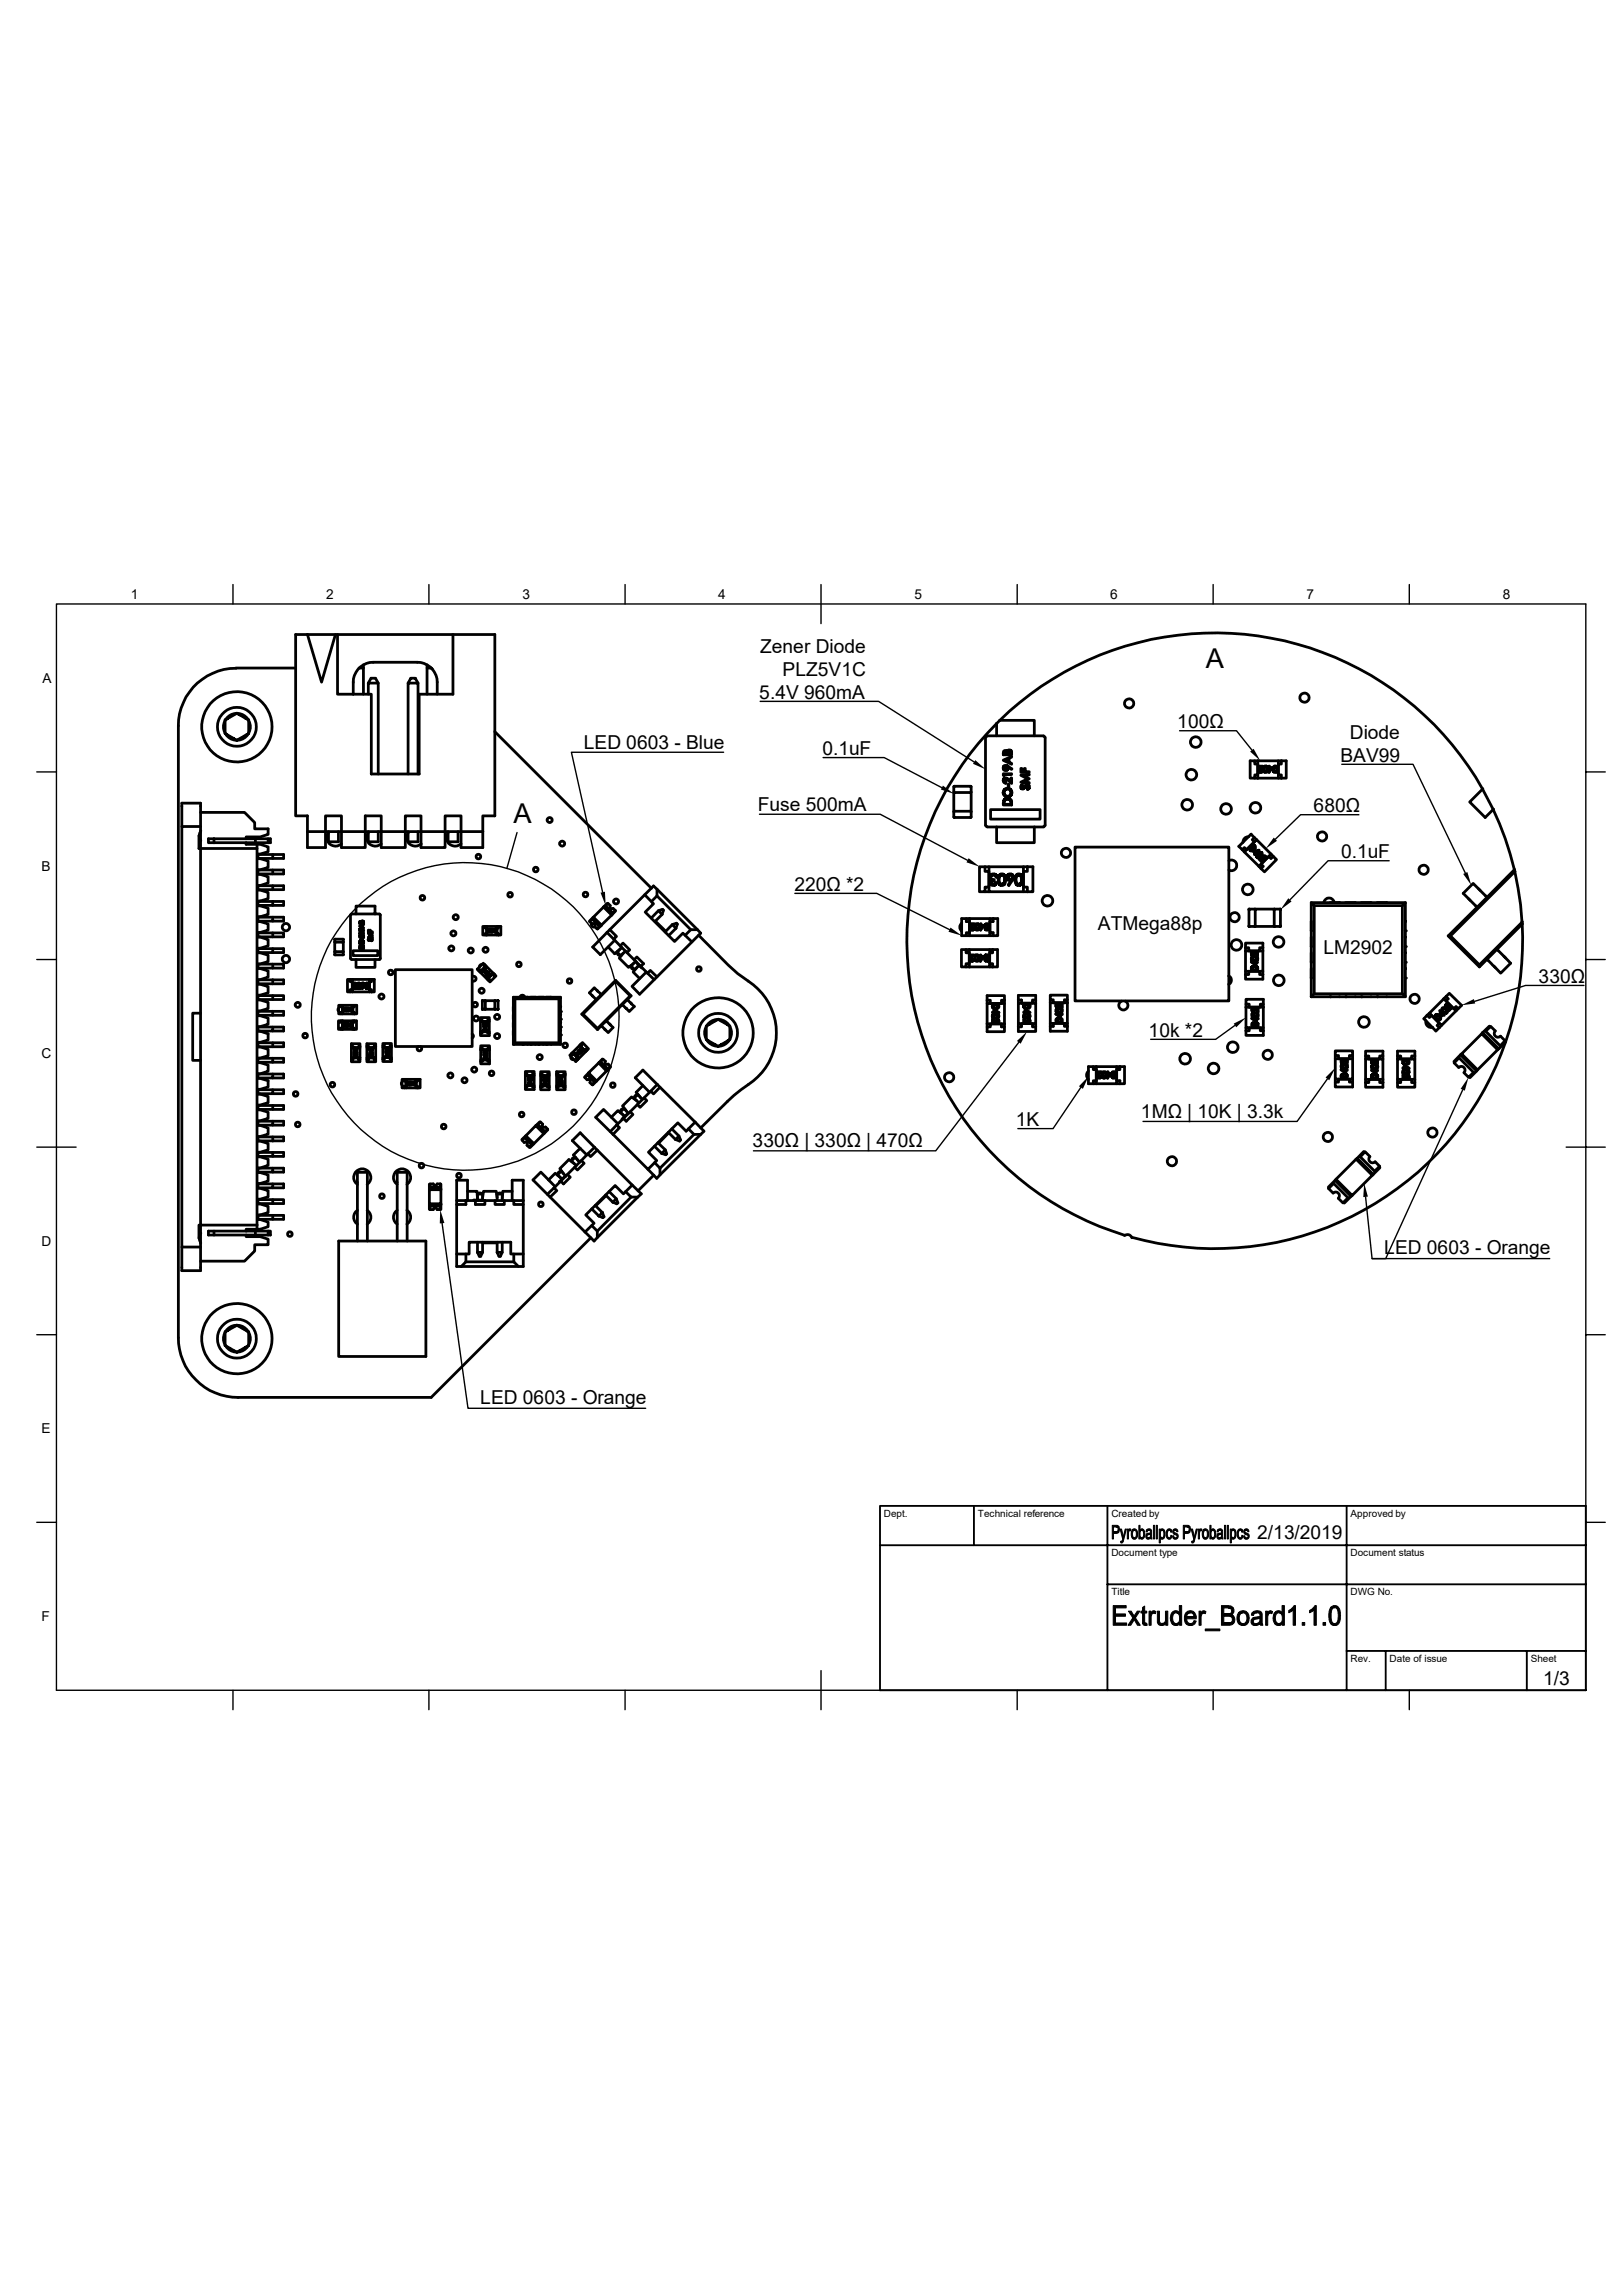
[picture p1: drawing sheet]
<svg xmlns="http://www.w3.org/2000/svg" width="297mm" height="420mm" viewBox="0 0 297 420" stroke-linecap="round" stroke-linejoin="round" font-family="sans-serif">
<defs><g id="words">
<g font-size="5">
<text x="220.6" y="122.3">A</text>
<text x="93.9" y="150.6">A</text>
</g>
<g font-size="3.5">
<text x="139.1" y="119.4">Zener Diode</text>
<text x="143.2" y="123.7">PLZ5V1C</text>
<text x="138.9" y="127.8">5.4V 960mA</text>
<text x="106.8" y="137.2">LED 0603 - Blue</text>
<text x="215.4" y="133.2">100Ω</text>
<text x="247" y="135.2">Diode</text>
<text x="150.5" y="138.1">0.1uF</text>
<text x="245.3" y="139.4">BAV99</text>
<text x="138.7" y="148.5">Fuse 500mA</text>
<text x="240.4" y="148.6">680Ω</text>
<text x="245.4" y="157">0.1uF</text>
<text x="145.4" y="163">220Ω *2</text>
<text x="200.9" y="170.2">ATMega88p</text>
<text x="242.2" y="174.7">LM2902</text>
<text x="281.6" y="179.8">330Ω</text>
<text x="210.2" y="189.7">10k *2</text>
<text x="137.7" y="209.9">330Ω | 330Ω | 470Ω</text>
<text x="185.9" y="206.1">1K</text>
<text x="208.8" y="204.5">1MΩ | 10K | 3.3k</text>
<text x="253.3" y="229.6">LED 0603 - Orange</text>
<text x="87.9" y="257">LED 0603 - Orange</text>
<text x="230.1" y="281.7">2/13/2019</text>
<text x="282.4" y="308.4">1/3</text>
</g>
<g font-size="2.5">
<text x="24" y="109.6">1</text>
<text x="59.7" y="109.6">2</text>
<text x="95.6" y="109.6">3</text>
<text x="131.4" y="109.6">4</text>
<text x="167.3" y="109.6">5</text>
<text x="203.2" y="109.6">6</text>
<text x="239.1" y="109.6">7</text>
<text x="275" y="109.6">8</text>
<text x="7.7" y="125">A</text>
<text x="7.6" y="159.3">B</text>
<text x="7.6" y="193.7">C</text>
<text x="7.6" y="228">D</text>
<text x="7.6" y="262.3">E</text>
<text x="7.6" y="296.6">F</text>
</g>
<g font-size="1.8">
<text x="161.8" y="277.6">Dept.</text>
<text x="178.9" y="277.6">Technical reference</text>
<text x="203.4" y="277.6">Created by</text>
<text x="247.1" y="277.6">Approved by</text>
<text x="203.4" y="284.8">Document type</text>
<text x="247.1" y="284.8">Document status</text>
<text x="203.4" y="292">Title</text>
<text x="247.1" y="292">DWG No.</text>
<text x="247.1" y="304.2">Rev.</text>
<text x="254.3" y="304.2">Date of issue</text>
<text x="280.1" y="304.2">Sheet</text>
</g>
</g></defs>
<g fill="none" stroke="#000" stroke-width=".51">
<path d="M54.1 116.1h36.5v33.2h-2.3v5.8h-3.9v-5.8h-3v5.8h-4.4v-5.8h-2.8v5.8h-4.4v-5.8h-3v5.8h-4.3v-5.8h-2.9v5.8h-3.3v-5.8h-2.2zM56.3 116.1l2.5 8.7 2.6-8.7M61.8 116.1v10.9h2.8M82.9 116.1v10.9h-6.2v14.6h-8.8v-14.6h-3.3M41.2 131.7l1.6-.9a.65 .65 0 0 1 1.1 .1l1.6 .8v2.5l-1.7 1.1a.54 .54 0 0 1-.9-.1l-1.7-1zM43.2 122.3a10.5 10.5 0 0 0-10.6 10.5v112a11 11 0 0 0 11 10.9h35.3l29.2-29.2M43.2 122.3h10.9M64.6 127a5.8 5.8 0 0 1 .6-4 3.7 3.7 0 0 1 3.1-1.8h8.1a3.6 3.6 0 0 1 3.6 3.6v2.2M65.7 122.3h.8M66.5 121.7v5.3M67.4 127v-2h1.8v16.6M67.4 125l.5-.9h.8l.5 .9"/>
<path d="M74.7 125l.5-.9h.8l.5 .9M78.1 121.7v5.3M78.1 122.3h.9l.1 .2M90.6 133.9l28.6 28.7M180.3 135v16M180.4 135l.2-.3h10.4l.2 .3M182.4 132.4a56.3 56.3 0 0 0 23.4 93.7M182.4 132.4v2.3M183 131.8a56.3 56.3 0 0 1 93.9 26.4 56.3 56.3 0 0 1-69.8 68.2M183 131.8h6.3v2.9M183 131.8l-.6 .6M183.6 139.1l1.5-.7v.2l-.4 .2v.7l.4 .2v.2z"/>
<path d="M183.7 137.5l.2-.1 .4 .1 .3-.3h.2l.3 .3v.6h-1.5zM183.8 137.6l.3-.1 .2 .5h-.5zM183.9 139.1l.6-.2v.5zM184.5 137.5h.4l.1 .5h-.6zM191.3 135v16M228.8 139.2h.8v.6h.6v2h-.6v.6h-.8zM229.6 139.2h.6M230.2 139.2h3.7v3.2h-3.7M230.2 139.2v3.2M233.9 139.2h1.5v3.2h-.9M234.5 139.2v.6h-.6v2h.6v.6M33.3 151.3v-4.3h3.4v77.2h10.3"/>
<path d="M36.4 152.9v2.4h10.6M36.4 153l.3 .8M36.7 151.3h-3.4v76.9h3.4M36.7 148.7h8l1.9 1.8v1.2h2.5v1l-1.5 .5h-2.6v.3M36.7 152.1l-.3 .8M38.1 153.5h11.4v.7h-11.4zM39.2 153.5v.7M45 154.2v.3h2M46.7 153.5v.7M47 154.5h.6l1.5 .5v.9l-1.5 .4h-.4v.8h.4l1.5 .5v1.2l-1.5 .4h-.4v.8h.4l1.5 .4v1.2l-1.5 .5h-.4v.8h.4l1.5 .4v1.2l-1.5 .4h-.4v.9h.4l1.5 .4v1.1l-1.5 .5h-.4v.9h.4l1.5 .4v1.1l-1.5 .4h-.4v.9h.4l1.5 .5v1.1l-1.5 .4h-.4v.9h.4l1.5 .4v1.2l-1.5 .4h-.4v.9h.4l1.5 .4v1.1l-1.5 .5h-.4v.8h.4l1.5 .5v1.1l-1.5 .4h-.4v.9h.4l1.5 .4v1.2l-1.5 .4h-.4v.9h.4l1.5 .4v1.2l-1.5 .4h-.4v.8h.4l1.5 .5v1.1l-1.5 .5h-.4v.8h.4l1.5 .4v1.2l-1.5 .4h-.4v.9h.4l1.5 .4v1.1l-1.5 .5h-.4v.9h.4l1.5 .4v1.1l-1.5 .4h-.4v.9h.4l1.5 .5v1.1l-1.5 .4h-.4v.9h.4l1.5 .4v1.2l-1.5 .4h-.4v.9h.4l1.5 .4v1.2l-1.5 .4h-.4v.8h.4l1.5 .5v1.1l-1.5 .5h-.4v.8h.4l1.5 .4v1.2l-1.5 .4h-.4v.9h.4l1.5 .4v1.2l-1.5 .4h-.4v.9h.4l1.5 .4v1.1l-1.5 .5h-.4v.8h.4l1.5 .5v1.1l-1.5 .4h-.4v.9h.4l1.5 .4v.9l-1.5 .5h-.6M47 154.5v70.5M47.2 156.4h4.7v.7h-4.7"/>
<path d="M47.2 159.2h4.7v.7h-4.7M49.1 153.5v.7M49.9 156.4v.7M49.9 159.2v.7M56.3 152.2h32M60.1 152.4a1.57 1.57 0 0 0 .3 2.1 1.57 1.57 0 0 0 2.1-.1M60.1 152.2v1.9h1.8v-1.9M67.4 152.4a1.57 1.57 0 0 0 .2 2.1 1.57 1.57 0 0 0 2.2-.1M67.4 152.2v1.9h1.8v-1.9M74.7 141.6v-16.6h1.8v16.6M74.7 152.2v1.9h1.8v-1.9M74.7 152.4a1.57 1.57 0 0 0 .3 2.1 1.57 1.57 0 0 0 2.1-.1"/>
<path d="M82 152.4a1.57 1.57 0 0 0 .2 2.1 1.57 1.57 0 0 0 2.2-.1M82 152.2v1.9h1.8v-1.9M174.5 145h3.2v3.5h-3.2zM174.6 145v-1.1h3v1.1M174.6 148.5v1.1h3v-1.1M179.2 158.6h1.1v.9h.7v2.8h-.7v.9h-1.1zM180.3 158.6h.7M180.4 151l.2 .3M180.6 151.3h10.4M181 158.6h6.3v4.6h-6.3zM181.3 148.2h9v1.7h-9zM182.4 151.3v2.9h6.9v-2.9"/>
<path d="M183.6 141.6h1.5v.1h-1.3v.3l-.2-.1zM183.6 142.5l.3-.1h.4l.7 .6v-.6h.1v1l-.7-.7a.34 .34 0 0 0-.6 0 .34 .34 0 0 0 .3 .5v.1l-.4-.1-.1-.4zM183.7 140.2l.5-.1 1 .6-.1 .1-.6-.4-.1 .4-.2 .2h-.3l-.3-.2zM183.8 140.3l.1-.1 .4 .1v.4l-.2 .2-.2-.1zM183.8 146.3l.4-.2 .7 .1 .2 .4v.7h-1.5zM183.9 146.4l.3-.2 .5 .1 .3 .3v.6h-1.2zM184.5 143.5h.1v.6h-.1zM186.1 160l.5-.1 .3 .3a1.71 1.71 0 0 1 0 1.6l-.6 .3-.5-.6v-.9zM186.8 140.6h.2v.6h.5v-.6h.1v.6h.7v.2h-1.5zM186.8 141.9l1.5-.2v.1l-1.1 .1 1.1 .6-1.1 .6 1.1 .1v.2l-1.5-.2 1.3-.7zM186.9 143.8l.1-.2 .2 .2a.23 .23 0 0 0-.3 .3 .23 .23 0 0 0 .4 0l.4-.4 .4-.1 .2 .2 .1 .4-.4 .3v-.1l.2-.3-.1-.3-.2-.1-.3 .3a.47 .47 0 0 1-.6 .4l-.2-.3zM187.3 158.6h1.7v4.6h-1"/>
<path d="M188 158.6v.9h-.7v2.8h.7v.9M191.2 151l-.2 .3M196.7 155h28.2v28.2h-28.2zM224.9 157.5a.97 .97 0 0 1 1.4 .9 .97 .97 0 0 1-1.4 .8M227.3 155.5l.4 .4M228.5 153.1a.98 .98 0 0 0-1 1.1M228.9 155.2l.4-.4 .3 .2-.2 .4-.2 .2-.4-.1zM228.9 154.9l.4-.2 .4 .2v.4l-.5 .4h-.3l-.2-.2v-.3zM229.3 155.8l1.1-.2-.5 .6 .1 .1-.4 .1h-.1l.2-.2zM229.5 153.3l-.3 .4 .3 .4-1.4 1.4-.4-.4-.4 .4M229.5 153.3l-.6-.6-2.2 2.2 .6 .6M229.5 153.3l.5 .4"/>
<path d="M229.6 155.9l.6-.2-.4 .4zM229.6 142.4h.6M230.1 156.4l.5-.4 .2 .2v.3l-.4 .4-.4-.1zM230.2 156.2l.3-.2h.3l.2 .2v.2l-.5 .5-.3 .1-.3-.2zM230.3 140.2h.8l-.6 .7a.25 .25 0 0 0 .1 .4 .25 .25 0 0 0 .3-.3l.2 .1-.3 .3h-.3l-.2-.2 .1-.4 .4-.5zM230.4 157.2l1-.1a.25 .25 0 0 0 0-.4 .25 .25 0 0 0-.3 .1v-.2h.3a.37 .37 0 0 1 .2 .4 .37 .37 0 0 1-.3 .3h-.7l.4 .4-.1 .1zM230.4 158.5l.4 .5M230.8 158.2l1.4-1.5 .4 .4 .4-.4 .6 .6-2.2 2.3-.6-.6 .4-.5zM231.3 140.3l.2-.1 .4 .1 .1 .7-.2 .3h-.5l-.1-.4zM231.4 140.4l.3-.1 .2 .2v.6l-.3 .2-.3-.3zM232.2 140.2h.1v.3h.6l-.7 .9v-.8h-.1zM232.3 140.6h.4l-.4 .5z"/>
<path d="M232.6 156.3l-2.6-2.6-2.3 2.2 2.7 2.6M232.6 156.3l-2.2 2.2M232.6 156.3l.4 .4M233.2 140.3h.3l.1 .2v.5l-.2 .3-.3-.2zM233.2 140.2h.3l.2 .3v.6l-.2 .3-.4-.1-.1-.3v-.5zM233.9 142.4h.6M271.4 144.4l-2.5 2.4 2.9 2.8 1.5-1.5M277.2 159.1l-12.2 12.2M277.2 159.5l-11.8 11.8M47.2 170.7h4.7v.8h-4.7M47.2 176.4h4.7v.8h-4.7M47.2 162.1h4.7v.7h-4.7"/>
<path d="M47.2 165h4.7v.7h-4.7M47.2 167.9h4.7v.7h-2M47.2 173.6h4.7v.7h-2M47.2 179.3h4.7v.7h-4.7M49.9 167.9v.7h-2.7M49.9 173.6v.7h-2.7M49.9 162.1v.7M49.9 165v.7M49.9 170.7v.8M49.9 176.4v.8M49.9 179.3v.7M61.3 172.4h1.5v1.8h-1.5z"/>
<path d="M61.3 172.4v-.5h1.5v.5M61.3 174.2v.6h1.5v-.6M63.6 179.2h.5v.5h.4v1.4h-.4v.4h-.5zM64.1 179.2h.4M64.1 167.4v8M64.2 175.4l.1 .2M64.3 175.6h5.2M64.3 167.3h5.2M64.3 167.3l-.1 .1M64.5 179.2h3.1v2.3h-3.1zM64.6 174h4.5v.9h-4.5zM65.2 167.3v-1.5h3.4v1.5"/>
<path d="M65.2 175.6v1.4h3.4v-1.4M65.4 180l.2-.1a.53 .53 0 0 1 .4 .4 .53 .53 0 0 1-.1 .5l-.4 .1-.2-.2v-.6zM65.8 169.5l.7-.4-.2 .2v.4l.2 .1zM65.8 170.7l.7 .1-.6 .1zM65.8 171.2l.3-.1 .4 .4v-.4v.5l-.3-.3a.2 .2 0 0 0-.4 0 .19 .19 0 0 0 .2 .3l-.2-.1zM65.8 168.7l.7-.1v.4h-.7zM65.9 170.1h.2v.2h-.2zM65.9 172.2l.4-.2 .2 .3v.3l-.1 .2h-.4a.44 .44 0 0 1-.1-.6zM65.9 170h.2l.4 .3-.3-.2v.2l-.3 .1-.1-.1zM65.9 173.1h.6v.5h-.7zM65.9 168.7h.2v.2h-.2zM65.9 173.1h.4l.2 .4h-.6z"/>
<path d="M66 169.5l.2-.1v.2zM66 172.2h.4a.36 .36 0 0 1-.2 .6 .38 .38 0 0 1-.2-.6zM66 171.5v.1M66.2 180a.35 .35 0 0 1 .5 0 .35 .35 0 0 1-.1 .5l-.4 .4 .3-.4-.4-.1zM66.2 171.7l.1 .3zM66.2 168.7h.3v.2h-.3zM67.4 170.2l.1 .3h.2l.1-.3v.3l.4 .1h-.8zM67.4 170.9l.8-.1-.6 .1 .6 .3-.6 .3 .6 .1-.8-.1 .6-.3zM67.4 171.8h.2l-.2 .2h.2l.3-.3h.2v.4h-.2l.2-.3h-.2a.23 .23 0 0 1-.3 .3 .23 .23 0 0 1-.2-.3zM67.6 179.2h.9v2.3h-.5M68 179.2v.5h-.4v1.4h.4v.4M69.5 167.3l.1 .1v8l-.1 .2"/>
<path d="M72.3 177.5h14.1v14h-14.1zM86.4 178.7a.48 .48 0 0 1 .6 .1 .48 .48 0 0 1 .1 .5l-.4 .3-.3-.1M87.8 177.9l1.1-1.1 1.4 1.3-1.1 1.1zM88.2 176.5l-.4 .2-.1 .3M88.3 169.5h.5v.3h.3v1.1h-.3v.2h-.5zM88.4 177.5l.2-.2 .2 .1v.1l-.3 .3-.1-.1zM88.5 177.3h.3l.1 .1-.3 .4-.3-.1zM88.6 177.8l.6-.1-.4 .4zM88.7 176.6l-.1 .2 .1 .2-.6 .7-.3-.2-.2 .2M88.7 176.6l-.3-.3-1.1 1.1 .5 .5M88.7 176.6l.2 .2M88.8 177.8h.3l-.2 .2z"/>
<path d="M88.8 169.5h.3M88.8 171.1h.3M89 178.2l.2-.2h.2l-.2 .4h-.2zM89.1 178l.1-.1 .3 .1-.1 .3-.2 .1h-.3zM89.1 169.5h1.8v1.6h-1.8M89.1 169.5v1.6M89.2 178.6l.5-.1v-.1l-.2-.1v-.1l.3 .1-.1 .3h-.4l.2 .2zM89.2 170h.3l-.3 .3v.3l.3-.2-.1 .2-.2-.1v-.2l.2-.2zM89.2 179.2l.2 .2M89.4 179l.7-.7 .2 .2 .2-.2 .3 .3-1.1 1.1-.3-.3 .2-.2zM89.6 170.1l.1-.1a.3 .3 0 0 1 .3 .2 .3 .3 0 0 1-.1 .3l-.3 .1zM89.7 170.1h.1l.1 .1-.1 .4-.2-.2z"/>
<path d="M90.1 170v.1h.3l-.3 .5zM90.1 170.2h.2l-.2 .3zM90.3 178.1l.2 .2M90.5 170.1l.1-.1a.33 .33 0 0 1 .3 .2 .33 .33 0 0 1-.1 .4l-.3-.1zM90.6 170.1l.2 .1-.1 .4-.2-.2zM90.9 169.5h.8v1.6h-.5M90.9 171.1h.3M91.2 169.5v.3h-.3v1.1h.3v.2M107.9 168.7l.5-.5 1.3 1.3-.5 .5-.4-.4 .1-.4-.4-.2-.2 .1zM108.2 169a.48 .48 0 0 0 .1 .5 .48 .48 0 0 0 .6 .1M108.5 167.9l-.6 .7M108.6 167.9h-.1l1.5 1.5"/>
<path d="M110 169.4l-.7 .6v-.1M110.1 169.3l-.1 .1M110.4 166l.1-.1 1.5 1.5-.1 .1M110.4 166l-1.8 1.9 1.5 1.4 1.8-1.8M110.4 166l1.5 1.5M111.1 170.6l7.4 7.5M111.1 170.6l-2.6 2.7 1.4 1.4 2.6-2.6M111.2 165.4l-.7 .5M111.3 165.3l.4 .4-.1 .2 .2 .4 .4-.1 .4 .4-.5 .5-1.3-1.3zM111.3 173.3l1.2 1.2 1-.9M111.6 170.1l1.2 1.3-.5 .5M112.5 166.7l.1 .1-.6 .6"/>
<path d="M112.6 179.4l-6.1 6.2M112.6 179.6v-.2l2.9 2.8h-.2M112.9 174.2a.66 .66 0 0 0 .7 .7M113.5 173.1l.5-.5 1.2 1.2-.5 .5M113.8 173.4l-.9 .8 .7 .7 .9-.9M114.1 174.4l-.8 .9 1.7 1.7 1-.7M115.4 176.7a.66 .66 0 0 0 .8 .8M116 175.6l.5-.5 1.3 1.3-.5 .5M116.3 175.9l-.8 .9 .6 .6 .8-.8M116.4 176l.7 .8M116.8 176.8l-.9 1.1 1.2 1.2M117.1 176.7v.1l.4 .3"/>
<path d="M118 163.7l1.6 1.7-1.5 1.5 5.3 5.4 1.6-1.5 1.6 1.6-6.4 6.4-1.2-1.2-.5 .5M118.3 177.9l-2.6 2.6 1.4 1.4 3.1-3.1M118.5 178.1l1.2 1.2M119.9 168.6l1.9 1.8M120.2 162.7v1.3l-1 1M120.2 164l6.2 6.1M120.5 166.7l.7-.3 .2 .2-.2 .7zM120.5 166.7l-1.3 1.3M121.2 167.3l-1.4 1.4M123 169.2l.8-.2 .2 .1-.3 .8zM123 169.2l-1.3 1.4M123.7 169.9l-1.3 1.3"/>
<path d="M125.4 171.2l1-1.1h1.2l.6 .7-1.6 1.6M127.6 170.1l-8-8-8.5 8.5M127.8 171.2l5.5 5.4 1.7 1.6a17.2 17.2 0 0 1 5.1 4.5 11.3 11.3 0 0 1-3.2 15.8 45.7 45.7 0 0 0-8.7 7.9M175.9 173.8h.9v.6h.6v2h-.6v.6h-.9zM176 168.1h.8v.6h.6v2h-.6v.5h-.8zM176 168.9a1 1 0 0 0 0 1.5M176.8 173.8h.6M176.8 177h.6M176.8 168.1h.6M176.8 171.2h.6M177.4 173.8h3.7v3.2h-3.7M177.4 173.8v3.2"/>
<path d="M177.4 168.1h3.7v3.1h-3.7M177.4 168.1v3.1M177.5 174.8h.8l-.7 .6a.27 .27 0 0 0 .2 .4 .27 .27 0 0 0 .3-.2 .31 .31 0 0 1-.2 .3 .31 .31 0 0 1-.4-.2v-.3l.5-.5h-.5zM177.5 169h.8l-.6 .8 .1 .3h.3l.2-.3-.2 .4a.37 .37 0 0 1-.5-.1 .37 .37 0 0 1 .1-.5l.4-.4h-.6zM178.5 174.8l.4-.1 .2 .2 .1 .7a.43 .43 0 0 1-.7 .3l-.1-.3v-.6zM178.6 169.1l.4-.1 .2 .3v.6l-.3 .3h-.2l-.2-.2-.1-.6zM178.6 174.9l.3-.1 .1 .2v.6l-.1 .2-.4-.2zM178.6 169.2h.3a.59 .59 0 0 1 .2 .8l-.2 .1-.3-.1zM179.4 174.8l.1 .2h.5l-.6 .9v-.8h-.2v-.1h.2zM179.5 169v.3h.6l-.6 .9v-.8h-.2l.2-.1zM179.5 175.1h.3l-.3 .5zM179.5 169.4h.4l-.4 .5z"/>
<path d="M180.3 174.8l.3-.1a.84 .84 0 0 1 .2 1.1l-.1 .1a.42 .42 0 0 1-.6-.4zM180.3 163.2h.7M180.3 175l.3-.2 .2 .2v.6l-.2 .2-.3-.1zM180.3 169.2l.4-.2 .2 .2 .1 .7-.3 .3h-.3l-.2-.3zM180.3 169.3a.26 .26 0 0 1 .3-.2 .26 .26 0 0 1 .2 .2v.7l-.3 .1-.2-.3zM181.1 173.8h1.4v3.2h-.8M181.1 177h.6M181.1 168.1h1.5v3.1h-.9M181.1 171.2h.6M181.2 160.2l.3-.2 .5-.1 .5 .5v.1h-.2l-.3-.4h-.4l-.2 .2-.1 .4 .3 .3h.3v.2l-.5 .1v.4l.5 .1 .5-.3-.3 .5h-.5a.55 .55 0 0 1-.3-.8l.1-.1-.3-.4zM181.7 173.8v.6h-.6v2h.6v.6M181.7 168.1v.6h-.6v2h.6v.5"/>
<path d="M182.8 160.2l.4-.3h.3l.3 .3a1.71 1.71 0 0 1 0 1.6l-.6 .3-.4-.3-.1-.4v-.9zM183 160.3l.1-.1a.43 .43 0 0 1 .6 .2l.2 .6-.1 .5-.2 .3h-.4l-.2-.1-.2-.4v-.6zM184.3 160.2l.4-.3h.3l.3 .2a.59 .59 0 0 1 0 .8l-.7 1.2-.1-.2 .5-.8h-.4l-.3-.2zM186.1 160.3l.1-.1a.43 .43 0 0 1 .6 .2l.1 .5v.6l-.2 .3h-.4l-.4-.5v-.6zM187.3 163.2h.7M224.8 178.6a.83 .83 0 0 1 .5 .8 .83 .83 0 0 1-.5 .7M227.9 174v3.8h3.2v-3.8M227.9 173.4h.6v.6h2v-.6h.6M227.9 173.4v-.8h3.2v1.4M227.9 178.4h.6v-.6h2v.6h.6M227.9 174h3.2M227.9 173.4v.6"/>
<path d="M227.9 177.8v.6M228.6 169.5h.1M228.6 166.4v.1M229 177l.3-.2h.6l.2 .2 .1 .3-.2 .2-.7 .1-.3-.2zM229 176.1h.7l.2-.2v.2h.2h-.2v.6zM229 175.2l.3-.2h.5l.4 .3v.3l-.4 .2h-.5l-.3-.2zM229 174.3l.4-.1 .6 .5 .1-.5v.7l-.7-.6-.3 .1v.3l.3 .2-.3-.1-.1-.1zM229.1 175.3l.3-.2 .3 .1a.26 .26 0 0 1 .3 .2 .26 .26 0 0 1-.3 .3 .39 .39 0 0 1-.5-.1zM229.2 177h.7l.1 .3-.1 .2h-.6l-.2-.2zM229.3 176.1h.4v.4zM229.6 166.4l.1 .1M229.7 166.4h3.5v3.1h-3.5z"/>
<path d="M229.7 166.4h-1.1v3.1h1.1M229.7 169.5h-.1M231.1 177.8v1.4h-3.2v-.8M233.2 166.4h1.1v3.1h-1.1M233.2 169.5h.1M233.3 166.4l-.1 .1M234.2 166.4l.1 .1M234.3 169.5h-.1M239.9 165.2h17.3M239.9 174.4l.1 1.7M239.9 168.6l.1 1.7M239.9 171.5l.1 1.7"/>
<path d="M239.9 177.3l.1 1.7M240.5 165.7h16.1M242.2 165.2a.98 .98 0 0 1 1-.9 .98 .98 0 0 1 1 .9M256.6 165.7l.6-.5v17.2l-.6-.5zM257.2 176.1h.1M257.2 173.2h.1M257.2 170.3h.1M257.2 179h.1M257.2 177.3h.1M257.2 168.6h.1M257.2 171.5h.1M257.2 174.4h.1"/>
<path d="M270.7 176.6l-5.3-5.3h-.4l5.7 5.7M272.1 164.2l-2.5-2.5-1.8 1.8 2.5 2.5M273.9 173.7l2.5 2.6-1.8 1.8-2.5-2.5M278.6 168.7l-7.9 7.9v.4l3.2-3.3M278.6 169.1l-4.7 4.6M36.7 185.4h-1.4v8.7h1.4M47.2 182.2h4.7v.7h-4.7M47.2 188h4.7v.7h-2M47.2 185.1h4.7v.7h-2M47.2 190.8h4.7v.8h-4.7M47.2 193.7h4.7v.7h-2M47.2 196.6h4.7v.7h-2"/>
<path d="M47.2 199.4h4.7v.8h-2M49.9 199.4v.8h-2.7M49.9 196.6v.7h-2.7M49.9 193.7v.7h-2.7M49.9 188v.7h-2.7M49.9 185.1v.7h-2.7M49.9 182.2v.7M49.9 190.8v.8M61.9 186.8h.5v.3h.3v1h-.3v.3h-.5zM62 184h.4v.3h.3v1h-.3v.2h-.4zM62 184.4l-.2 .3 .2 .4M62.4 186.8h.3"/>
<path d="M62.4 188.4h.3M62.4 184h.3M62.4 185.5h.3M62.7 186.8h1.8v1.6h-1.8M62.7 186.8v1.6M62.7 184h1.9v1.5h-1.9zM62.7 187.3h.4l-.3 .4 .1 .1 .2-.1-.1 .2-.3-.1 .3-.4zM62.7 184.4h.5l-.4 .4 .1 .2 .2-.1-.1 .1h-.2v-.3l.2-.2zM63.2 187.4l.2-.1 .1 .1v.5l-.3-.1zM63.2 187.4h.3l-.1 .4h-.2zM63.2 184.5l.3-.1v.2a.3 .3 0 0 1 .1 .3 .3 .3 0 0 1-.3 .1zM63.3 184.5h.2a.22 .22 0 0 1 .1 .3 .22 .22 0 0 1-.4 .1z"/>
<path d="M63.7 187.3v.1h.3l-.3 .5zM63.7 187.5h.2l-.2 .2zM63.7 184.4l.1 .2h.2l-.3 .4zM63.8 184.7h.1l-.1 .2zM64.1 187.3h.1a.34 .34 0 0 1 .2 .5h-.3zM64.1 181.5h.4M64.1 184.5h.3a.3 .3 0 0 1 0 .4 .3 .3 0 0 1-.3 .1zM64.1 187.4h.2a.25 .25 0 0 1 .1 .3 .25 .25 0 0 1-.2 .1zM64.2 184.5a.2 .2 0 0 1 .2 .3 .2 .2 0 0 1-.3 .1zM64.3 193.9h.3v-.3h1v.3h.3v.4h-1.6zM64.3 193.6v-1.9h1.6v1.9M64.3 191.5h.3v.2h1v-.2h.3"/>
<path d="M64.3 193.6h1.6M64.3 193.6v.3M64.5 186.8h.7v1.6h-.4M64.5 188.4h.3M64.6 184h.7v1.5h-.4M64.6 180l.3-.1 .3 .3-.2-.2a.23 .23 0 0 0-.4 .2 .23 .23 0 0 0 .3 .2l-.2 .2v.2h.2l.3-.1v.1l-.5 .1-.1-.1 .1-.3-.2-.2zM64.6 185.5h.3M64.8 192.8l.1-.1a.24 .24 0 0 1 .3 0 .24 .24 0 0 1 .1 .3l-.4 .1zM64.8 193.2l.3 .3 .2-.1-.1-.2h.1l.1 .3h-.2l-.3-.2-.1 .2zM64.8 192.9l.3-.2 .2 .3h-.4zM64.8 186.8v.3h-.3v1h.3v.3M64.8 192l.4-.1 .1 .2-.4 .1z"/>
<path d="M64.9 191.9a.26 .26 0 0 1 .4 0 .26 .26 0 0 1-.2 .4 .26 .26 0 0 1-.3-.4zM64.9 184v.3h-.3v1h.3v.2M64.9 192.3l.5 .3-.5 .1-.1-.1 .1-.1zM65 192.4l.2 .1h-.2zM65.4 180.1l.3-.1 .2 .1v.4l-.2 .3-.3-.1zM65.9 191.5v-.5h-1.6v.7M65.9 191.5v.2M65.9 193.6v.3M66.2 180.1l.3-.1 .1 .2a.22 .22 0 0 1-.2 .2 .22 .22 0 0 1-.2-.3zM66.9 180l.3-.1 .3 .1v.7l-.2 .2h-.2l-.2-.1zM67 180.1l.1-.1 .3 .1v.5l-.1 .2-.3-.1zM67.1 191.7h1.6v1.9h-1.6z"/>
<path d="M67.1 193.9h.3v-.3h1.1v.3h.2v.4h-1.6zM67.1 191.4h.3v.3h1.1v-.3h.2M67.1 193.6v.3M67.6 181.5h.4M67.6 192.8l.5-.1 .1 .3-.4 .1zM67.6 191.9l.5-.1 .1 .3-.1 .1h-.4zM67.6 193.1l.4 .4 .2-.1-.2-.2h.2v.3h-.3l-.2-.2-.1 .2zM67.7 192.8l.4-.1 .1 .3h-.4zM67.7 191.9a.25 .25 0 0 1 .3-.1 .25 .25 0 0 1 .2 .3l-.4 .1zM67.8 192.2l.4 .4h-.6l.2-.1zM67.8 192.4l.3 .1h-.3zM68.7 191.4v-.4h-1.6v.7"/>
<path d="M68.7 191.4v.3M68.7 193.6v.3M70.1 191.7h1.5v1.8h-1.5zM70.1 191h1.5v.4h-.2v.3h-1v-.3h-.3zM70.1 193.8h.3v-.3h1v.3h.2M70.1 191.4v.3M70.1 193.5v.3M70.6 192.7h.6h-.2v.3zM70.6 192.3l.5-.1 .1 .3-.5 .1zM70.6 191.8h.2l.3 .2 .1-.2v.4l-.4-.4-.1 .1 .1 .2h-.1zM70.6 193.2l.4-.1 .2 .2-.2 .2h-.3zM70.7 192.3h.4v.2h-.4z"/>
<path d="M70.7 193.2l.3-.1 .1 .2-.4 .1zM70.7 192.7h.3v.2zM71.6 193.5v.8h-1.5v-.5M71.6 191.4v.3M73.6 197.5h.4v.3h.3v1h-.3v.3h-.4zM73.6 198l-.2 .2 .2 .4M74 197.5h.3M74 199.1h.3M74.3 197.5h1.9v1.6h-1.9zM74.3 198h.5l-.4 .3 .1 .2 .2-.1-.1 .2-.2-.1v-.2l.2-.3zM74.8 198l.3 .1a.3 .3 0 0 1 .1 .3 .3 .3 0 0 1-.3 .2l-.1-.1zM74.9 198.1l.2-.1v.2l-.1 .3-.2-.1z"/>
<path d="M75.3 198l.1 .1h.2l-.3 .5zM75.4 198.2h.1l-.1 .3zM75.7 198h.3v.1a.3 .3 0 0 1-.2 .5l-.1-.1zM75.8 198.1a.2 .2 0 0 1 .2 .2 .2 .2 0 0 1-.2 .2zM76.2 197.5h.7v1.6h-.4M76.2 199.1h.3M76.5 197.5v.3h-.3v1h.3v.3M76.6 191.5l-.3 .4 .1 .2a.43 .43 0 0 0 .5 .2 .43 .43 0 0 0 .3-.4l-.3-.4M86.4 189.2l.3 .4-.3 .4M87.9 186.9h1.6v1.9h-1.6zM87.9 186.2h1.6v.4h-.3v.3h-1v-.3h-.3zM87.9 189.1h.3v-.3h1v.3h.3"/>
<path d="M87.9 186.6v.3M87.9 188.8v.3M88 191.4h1.6v.4h-.3v.3h-1v-.3h-.3zM88 192.1v1.9h1.6v-1.9M88 194.3h.3v-.3h1v.3h.3M88 192.1h1.6M88 191.8v.3M88 194v.3M88.3 184.7h.1M88.3 183.1v.1M88.5 188l.4-.1 .1 .1h-.1v.3zM88.5 188.4l.4-.1 .2 .3-.5 .1z"/>
<path d="M88.5 187.1l.2-.1 .3 .3v-.3v.4l-.3-.3h-.2l.1 .3zM88.5 187.5h.4l.2 .2-.5 .1zM88.5 193.1l.4-.1 .2 .2h-.2v.2zM88.5 193.6l.1-.1a.28 .28 0 0 1 .3 0 .28 .28 0 0 1 .1 .3h-.5zM88.5 187.6l.4-.1a.21 .21 0 0 1-.1 .3 .21 .21 0 0 1-.3-.2zM88.5 192.2h.2l.3 .2 .1-.2v.3l-.3-.3-.2 .1v.2zM88.5 188.5l.4-.1a.21 .21 0 0 1-.1 .3 .21 .21 0 0 1-.3-.2zM88.5 193.1h.1M88.6 192.7h.4a.22 .22 0 0 1-.1 .2 .22 .22 0 0 1-.3 0zM88.6 192.7l.4-.1 .1 .3-.2 .1h-.3zM88.6 193.6l.4-.1v.3h-.4zM88.6 188h.3v.2z"/>
<path d="M88.6 193.2h.3v.1zM88.7 192.5h.1M88.8 183.1v.1M88.8 183.1h1.8v1.6h-1.8zM88.8 183.1h-.5v1.6h.5M88.8 184.7h.1M89.5 188.8v.7h-1.6v-.4M89.5 186.6v.3M89.6 194v.7h-1.6v-.4M89.6 191.8v.3M90.6 183.1h.5v1.6h-.5M90.6 184.7h.1"/>
<path d="M90.6 183.1v.1M91.1 183.1v.1M91.1 184.7h.1M93.9 182.5h8.7M93.9 187.1l.1 .9M93.9 184.2l.1 .9M93.9 185.7l.1 .8M93.9 188.6l.1 .8M94.2 182.8l-.3-.3v8.6M94.2 182.8v8M94.2 182.8h8.1M95.1 182.5a.48 .48 0 0 1 .5-.4 .48 .48 0 0 1 .5 .4"/>
<path d="M95.7 191.1h.1M96.1 196.8h1.6v1.9h-1.6zM96.1 196.1h1.6v.4h-.2v.3h-1.1v-.3h-.3zM96.1 199h.3v-.3h1.1v.3h.2M96.1 196.5v.3M96.1 198.7v.3M96.5 191.1h.1M96.7 197.8l.4-.1 .1 .2h-.1v.2zM96.7 197.4l.5-.1 .1 .3-.5 .1zM96.7 198.3l.5-.1 .1 .3-.4 .1-.2-.1zM96.7 196.9h.2l.3 .2v-.2v.3l-.3-.3-.2 .1 .1 .2zM96.7 198.3l.5-.1v.3h-.4z"/>
<path d="M96.7 197.4h.4l.1 .2-.3 .1zM96.8 197.9h.3v.1zM97.1 191.1h.1M97.7 198.7v.7h-1.6v-.4M97.7 196.5v.3M98 191.1h.1M98.6 191.1h.1M98.9 196.9h1.6v1.8h-1.6zM98.9 196.1h1.6v.5h-.3v.3h-1v-.3h-.3zM98.9 199h.3v-.3h1v.3h.3M98.9 196.6v.3M98.9 198.7v.3"/>
<path d="M99.4 191.1h.1M99.4 197.9l.5-.1 .1 .1h-.1v.3zM99.4 198.3h.1a.27 .27 0 0 1 .4-.1 .27 .27 0 0 1 0 .4 .27 .27 0 0 1-.4-.1zM99.4 197l.3-.1 .3 .2v-.2v.4l-.3-.3-.2 .1 .2 .2-.2-.1zM99.5 197.4h.5a.28 .28 0 0 1-.2 .4 .28 .28 0 0 1-.3-.2zM99.5 197.4h.4l.1 .2-.4 .1zM99.5 198.3h.4l.1 .2h-.4zM99.6 197.9h.2v.2zM100 191.1h.1M100.5 198.7v.7h-1.6v-.4M100.5 196.6v.3M100.8 191.1h.1"/>
<path d="M101.9 196.9h1.5v1.8h-1.5zM101.9 199h.3v-.3h.9v.3h.3v.4h-1.5zM101.9 196.6h.3v.3h.9v-.3h.3M101.9 198.7v.3M102.3 182.8l.3-.3v8.6l-.3-.3zM102.3 190.8h-8.1l-.3 .3h8.7M102.3 197.9l.5-.1 .1 .3-.4 .1zM102.3 198.2l.4 .4 .2-.1-.2-.3 .1 .1 .1 .2-.2 .1-.3-.2-.1 .2zM102.4 197l.4-.1 .1 .3-.2 .1h-.3zM102.4 197.1l.4-.1 .1 .1-.4 .2zM102.4 197.9h.4a.22 .22 0 0 1-.2 .3 .22 .22 0 0 1-.2-.3zM102.4 197.4l.5 .3h-.6h.1z"/>
<path d="M102.5 197.4l.3 .3h-.3zM102.6 188h.1M102.6 186.5h.1M102.6 185.1h.1M102.6 189.4h.1M102.6 188.6h.1M102.6 184.2h.1M102.6 185.7h.1M102.6 187.1h.1M103.4 196.6v-.5h-1.5v.8M103.4 196.6v.3M103.4 198.7v.3"/>
<path d="M104.5 193.3l.1 .5 .4 .1M104.6 192.8l.2 .2 .1-.2 .8 .7-.2 .3 .2 .2M104.6 192.8l-.3 .3 1.1 1.2 .5-.5M104.8 192.6l1.3-1.3 1.1 1.1-1.3 1.4zM104.8 192.6l-.2 .2M105.3 192.8l.2-.1 .2 .2v.4h-.2l-.2-.3zM105.3 192.9h.3l.1 .2a.28 .28 0 0 1-.2 0 .28 .28 0 0 1-.2-.2zM105.7 192.4l.4 .4-.1-.1-.2 .3zM105.8 192.5l.2 .2-.2 .1zM105.9 192.2a.32 .32 0 0 1 .3-.1 .32 .32 0 0 1 .2 .3 .26 .26 0 0 1-.2 .2 .26 .26 0 0 1-.3-.2zM106 192.2h.2l.1 .4h-.2zM106.2 191.9l.3-.1 .1 .5 .2-.1-.2 .2-.1-.5h-.2v.2z"/>
<path d="M106.3 191.1l.3-.3 1.1 1.1-.3 .3-.2-.2-.2 .2-.7-.7 .2-.2zM106.3 191.1l-.2 .2M106.5 185.6h.2l2.6 2.6v.2zM107 197.2l.5-.5 1.3 1.3-.5 .5-.4-.4 .1-.2-.1-.3h-.5zM107.4 192.2l-.2 .2M107.6 196.5l-.5 .6M107.7 196.3l1.9-1.8 1.4 1.5-1.8 1.8zM107.7 196.3l-.1 .2 1.5 1.4 .1-.1M109.1 197.9l-.6 .6h-.1M109.6 194.4l1.5 1.5-.1 .1M109.6 194.4v.1M109.9 194.3l.5-.5 .4 .4-.1 .2 .2 .4 .4-.1 .4 .5-.4 .4z"/>
<path d="M110 182l-1.2-1.2-.9 .9 1.2 1.2M110.3 193.9l-.1-.1-.6 .6M111 186.8l1.2 1.2-.9 1-1.3-1.3M111.6 195.2l.1 .1-.6 .6M114.8 182.9l1.3 1.3-1 .9-1.2-1.2M115.3 182.2l-2.7-2.6-5.9 6M115.3 182.2l-6 6M115.5 182.2l-6.2 6.2M117.6 198.7l-1.2 1.2 .9 1.1M120.3 198.5l6.9 6.9M120.3 198.5l-7.4 7.4M120.3 198.5l-2.7-2.7-1.4 1.4 2.7 2.7"/>
<path d="M120.8 199l-1.2 1.2-.5-.5M133.5 187.8a2.46 2.46 0 0 0-3.7-.7 2.46 2.46 0 0 0 0 3.8 2.46 2.46 0 0 0 3.7-.7M133.5 187.8a2.31 2.31 0 0 1 0 2.4M133.6 187.8l-1.6-.9a.72 .72 0 0 0-.9-.2l-1.9 1.1v2.4l1.7 1a.7 .7 0 0 0 1.1-.1l1.6-.9M133.6 187.8v2.4M180.6 187.4v-3.8h3.2v3.8M180.6 187.9h.6v-.5h2.1v.5h.5v.9h-3.2zM180.6 183h.6v.6h2.1v-.6h.5M180.6 187.4h3.2M180.6 187.4v.5M181.6 186.4l.7 .7h.2l.2-.4-.3-.2a.4 .4 0 0 1 .3 .6l-.4 .1-.6-.5v.5h-.1zM181.7 185.7l.5-.2 .4 .1 .2 .2-.2 .5h-.7a.38 .38 0 0 1-.2-.6z"/>
<path d="M181.7 183.9l.8-.1 .3 .3-.2 .4-.7 .1a.43 .43 0 0 1-.2-.7zM181.7 184l.7-.1 .2 .1 .1 .3-.4 .2-.4-.1-.2-.1zM181.7 185.8l.7-.1 .3 .1v.3l-.2 .1h-.6l-.2-.1zM181.9 184.7l.9 .6h-.8v.2l-.4-.2v-.1h.3zM182 184.9l.5 .3h-.5zM183.8 183v-.8h-3.2v1.4M183.8 183v.6M183.8 187.4v.5M186.4 183.6h3.1v3.7h-3.1zM186.4 187.9h.5v-.6h2v.6h.6M186.4 187.3v1.5h3.1v-.9M186.4 183h.5v.6h2v-.6h.6"/>
<path d="M186.4 183.6v-1.4h3.1v1.4M187.3 186.4l.7 .7 .4-.2-.1-.3-.2-.1h.2a.36 .36 0 0 1 0 .7l-.4-.1-.4-.5v.6h-.2zM187.3 184h.1a.6 .6 0 0 1 .7-.2l.4 .3v.2l-.3 .2h-.7l-.2-.3zM187.4 185.7l.2-.2h.6l.2 .2 .1 .3-.2 .3h-.6l-.4-.3zM187.5 184l.2-.1a.44 .44 0 0 1 .7 .3l-.3 .2h-.4l-.2-.1zM187.5 185.8l.6-.2 .2 .2 .1 .2-.4 .2h-.4l-.2-.2zM187.6 184.7l.9 .6h-.8v.1l-.4-.1 .3-.1zM187.7 184.9l.5 .3h-.5zM189.5 187.3v.6M192.2 182.1h3.1v.9h-.5v.5h-2.1v-.5h-.5zM192.2 183.5v3.8h3.1v-3.8M192.2 187.8h.5v-.5h2.1v.5h.5"/>
<path d="M192.2 183.5h3.1M192.2 187.3v1.4h3.1v-1.4M192.2 183v.5M193.2 185.5h.8l.1-.1v.1h.3v.2h-.3v.5zM193.3 184.7l.2-.1h.6l.3 .2v.3l-.4 .2h-.4l-.4-.2zM193.3 183.8l.4-.1 .6 .5v-.5h.1v.7l-.8-.6-.3 .1v.3l.3 .2h-.2l-.2-.2zM193.3 186.5l.3-.2 .5 .1 .3 .1v.4l-.3 .2h-.6l-.3-.3zM193.3 184.8l.3-.1h.4a.28 .28 0 0 1 .3 .2 .28 .28 0 0 1-.2 .3h-.6zM193.4 186.5l.7-.1a.28 .28 0 0 1 .2 .3 .28 .28 0 0 1-.2 .3l-.7-.1zM193.5 185.7h.5v.3zM195.3 183v.5M199.2 196a1 1 0 0 0 0 1.5"/>
<path d="M200.1 195.2h.5M200.6 195.2h3.7v3.1h-3.7M200.6 195.7h-.5v-.5h-.9v3.1h1.4M200.6 197.8h-.5v.5M200.6 195.2v3.1M200.7 196.1h.8l-.6 .8 .1 .3h.3l.2-.3-.2 .4-.5-.2v-.2l.5-.6h-.6zM201.8 196.3a.28 .28 0 0 1 .3-.1 .28 .28 0 0 1 .2 .3v.6a.28 .28 0 0 1-.3 .1 .28 .28 0 0 1-.2-.2zM201.8 196.2l.4-.1 .2 .3v.6l-.3 .3a.42 .42 0 0 1-.5-.4v-.4zM202.6 196.1h.2v.3h.5l-.6 .9-.1-.8h-.1l.1-.1zM202.8 196.5h.3l-.3 .5zM203.5 196.2l.5-.1 .2 .3v.6l-.3 .3h-.2l-.2-.2-.1-.6zM203.6 196.3l.2-.1 .2 .2 .1 .5-.2 .3h-.2l-.2-.2z"/>
<path d="M204.3 195.2h1.5v3.1h-.9M204.3 198.3h.6M204.9 195.2v.5h-.6v2.1h.6v.5M205.2 183.2a.85 .85 0 0 0-.3 1.3 .85 .85 0 0 0 1.3 0 .85 .85 0 0 0-.3-1.3M228 184.3v3.8h3.2v-3.8M228 182.9h3.2v.9h-.6v.5h-2v-.5h-.6zM228 188.6h.6v-.5h2v.5h.6M228 184.3h3.2M228 183.8v.5M228 188.1v.5M229.1 184.7l.1-.2h.3l.6 .5v-.6h.2v.9l-.8-.7-.3 .2v.2l.2 .1v.1a.35 .35 0 0 1-.3-.5zM229.1 186.4h.7l.2-.2v.2h.3v.1h-.3v.5z"/>
<path d="M229.1 187.3l.3-.2 .6 .1 .3 .2v.2l-.3 .3h-.6l-.3-.2zM229.2 185.5l.3-.2 .5 .1 .2 .1 .1 .4a.86 .86 0 0 1-1.2 0v-.3zM229.2 187.4l.4-.2 .5 .1a.28 .28 0 0 1 0 .3 .28 .28 0 0 1-.2 .2l-.6-.1zM229.2 185.6l.7-.1h.2v.3l-.2 .2h-.5l-.2-.1zM229.4 186.5h.4v.3zM231.2 188.1v1.4h-3.2v-.9M231.2 183.8v.5M239.9 182.4h17.3M240.5 181.9v-16.2l-.6-.5v17.2M240.5 181.9l-.6 .5M240.5 181.9h16.1M244.3 192.3h3.2v.9h-.6v.6h-2v-.6h-.6z"/>
<path d="M244.3 193.8v3.7h3.2v-3.7M244.3 198h.6v-.5h2v.5h.6M244.3 193.8h3.2M244.3 193.2v.6M244.3 197.5v.5M245.4 195l.3-.2h.6l.2 .1 .1 .4-.2 .2h-.7l-.3-.1zM245.4 194.1l.4-.2 .7 .5v-.5v.7l-.6-.6a.27 .27 0 0 0-.4 .2 .27 .27 0 0 0 .3 .3h-.3zM245.4 195.7h.8l.1-.1 .2 .3h-.2v.5zM245.5 196.6l.3-.1 .5 .1 .2 .1 .1 .3-.3 .3h-.6l-.3-.2zM245.5 196.8l.2-.2h.6l.1 .1 .1 .3-.2 .2h-.6l-.2-.1zM245.6 194.9h.7l.2 .3-.2 .2h-.6l-.2-.2zM245.7 195.9h.5v.3z"/>
<path d="M247.5 197.5v1.4h-3.2v-.9M247.5 193.2v.6M249.9 193.8h3.2v3.7h-3.2zM249.9 192.4h3.2v.9h-.6v.5h-2v-.5h-.6zM249.9 198.1h.6v-.6h2v.6h.6M249.9 193.3v.5M249.9 197.5v.6M251 195.8h.7l.1-.1 .3 .3h-.3v.5zM251 195.1l.4-.3 .5 .1 .2 .1v.3l-.2 .3h-.5l-.4-.1zM251 194.1l.1-.1h.3l.6 .5 .1-.6v.8l-.7-.6-.4 .2 .1 .2 .2 .1v.1l-.1-.1a.36 .36 0 0 1-.2-.5zM251 196.8l.3-.2h.6l.2 .3v.2l-.3 .3h-.6l-.2-.3zM251.1 195.1l.7-.2 .2 .2a.48 .48 0 0 1-.3 .5 .48 .48 0 0 1-.5-.2z"/>
<path d="M251.1 196.8l.7-.1 .2 .2v.2l-.3 .2-.5-.1-.2-.2zM251.2 196h.5v.3zM253.1 197.5v1.5h-3.2v-.9M253.1 193.3v.5M255.7 193.8h3.2v3.7h-3.2zM255.7 198.1h.6v-.6h2v.6h.6v.9h-3.2zM255.7 193.3h.6v.5h2v-.5h.6M255.7 193.8v-1.4h3.2v1.4M255.7 197.5v.6M256.7 196l.4-.3 .4 .1a.35 .35 0 0 1 .4 .2 .35 .35 0 0 1-.2 .4l-.3 .2-.6-.1-.1-.2zM256.7 196.6l.7 .7a.25 .25 0 0 0 .4-.2 .25 .25 0 0 0-.3-.3v-.1l.3 .1 .1 .2-.2 .4h-.4l-.5-.5v.5h-.1zM256.7 194.2l.1-.1a.91 .91 0 0 1 1 0 .33 .33 0 0 1 .1 .4 .33 .33 0 0 1-.4 .2h-.7l-.1-.2z"/>
<path d="M256.8 194.3l.2-.2h.5l.2 .1 .1 .2-.2 .2h-.6l-.2-.1zM256.8 196l.8-.1 .2 .3-.3 .2h-.5l-.2-.1zM257 194.9l.9 .6h-.8v.2l-.4-.2v-.1h.3zM257.1 195.1l.5 .3h-.5zM258.9 197.5v.6M260.9 186.8a.99 .99 0 0 0 1.3 1.2M261.2 185.8l.4 .4 .4-.4 1.4 1.4-.4 .5 .4 .3M261.2 185.8l-.6 .6 2.2 2.3 1-1M261.6 185.4l-.4 .4M262.7 185.7h.1a.7 .7 0 0 1 .8 .6l-.2 .4-.3-.1-.5-.5zM262.7 185.8h.4l.3 .3 .1 .3-.4 .2-.3-.4zM263.5 185l.5 .5h.2l-.1 .1 .2 .2h-.1l-.1-.1-.4 .4z"/>
<path d="M263.6 185.2l.4 .4-.3 .2zM263.9 184.4h.1a.76 .76 0 0 1 .9 .6l-.1 .3-.2 .2a.71 .71 0 0 1-.7-1zM264 184.6l.2-.1 .4 .2 .2 .5-.2 .1h-.3l-.4-.4zM264.2 182.8l-2.6 2.6 2.2 2.3 2.6-2.7M264.2 182.8l2.2 2.2M264.6 183.8l.3-.1 .2 .2 .1 .8 .5-.3-.6 .6v-.9l-.2-.2h-.3v.5l-.1-.2zM264.6 182.4l.6-.6 2.3 2.2-.7 .6-.4-.4-.4 .4-1.4-1.4 .4-.4zM264.6 182.4l-.4 .4M266.8 184.6l-.4 .4M266.9 195.3l-.8-.8 .9-.9 2.7 2.7-1 .8-.8-.8M267 195.4a.66 .66 0 0 1 .9 0 .66 .66 0 0 1 0 .9M267.3 193l-1.2 1.3 .1 .1"/>
<path d="M267.5 192.9l3.6-3.7 3 2.9-3.7 3.7zM267.5 192.9l-.2 .1 2.9 3 .2-.2M270.2 196l-1.2 1.2-.1-.1M271.3 189l3 2.9-.2 .2M271.3 189l-.2 .2M272.7 187.9l-.2-.1-1.2 1.2M273.6 188.6l-.8-.8-.9 .9 2.6 2.7 .9-.9-.8-.8M273.6 188.7a.66 .66 0 0 0 0 .9 .66 .66 0 0 0 1 0M275.3 190.5l.2 .2-1.2 1.2M47.2 219.5h4.7v.8h-4.7M47.2 216.7h4.7v.7h-2M47.2 202.3h4.7v.7h-2"/>
<path d="M47.2 205.2h4.7v.7h-2M47.2 208.1h4.7v.7h-4.7M47.2 210.9h4.7v.7h-2M47.2 213.8h4.7v.7h-2M49.9 216.7v.7h-2.7M49.9 213.8v.7h-2.7M49.9 210.9v.7h-2.7M49.9 205.2v.7h-2.7M49.9 202.3v.7h-2.7M49.9 208.1v.7M49.9 219.5v.8M65.4 216.7a1.56 1.56 0 0 1-.3-2.3 1.56 1.56 0 0 1 2.4 0 1.56 1.56 0 0 1-.3 2.3"/>
<path d="M72.7 216.7a1.56 1.56 0 0 1-.3-2.3 1.56 1.56 0 0 1 2.3 0 1.56 1.56 0 0 1-.2 2.3M78.6 217.7h2.1v2.6h-2.1zM78.6 217.7v-.1h2.1v.1M78.7 216.7h-.1v.9M80 216.7l-.3 .3-.3-.1-.1-.2h-.6v.6h1.9v-.6h-.6M80.6 216.7h.1v.9M83.6 219.7h12.2M85.3 219.7v.7h-1.7v9.1h2.3v-2.2h7.6v2.2h2.3M85.6 218h1.7l.1 1.4M85.6 219.7v-3.7h-2v4.4M86.7 219.7h.5M87 219.7v.7h1.7v-.7"/>
<path d="M87.2 219.6l1 .1M87.3 218.5a.67 .67 0 0 1 1 .1M87.4 219.6v-1.1h.9v1.2M88.3 219.2l.2-1.2h2.3l.2 1.2M90.6 219.7v.7h1.7v-.7M91 219.7v-1.2h.9v1.2M91.9 218.5a.67 .67 0 0 0-1 .1M93.7 218h-1.7l-.1 1.4M93.7 219.7v-3.7h2.1v15.8h-12.2v-2.3M94 219.7v.7h1.8M95.5 208.7l.5-.5 1.3 1.4-.4 .4-.5-.4 .1-.2-.1-.4-.5 .1zM96.1 207.9l-.6 .6 .1 .1"/>
<path d="M96.2 207.9h-.1l1.5 1.5 .1-.1M97.6 209.4l-.6 .6-.1-.1M98 206l1.5 1.5-1.8 1.8-1.5-1.4zM98.2 205.9l1.4 1.5-.1 .1M98.2 205.9l-.2 .1M98.4 205.8l.5-.5 .4 .4v.5l.3 .1 .2-.1 .4 .4-.5 .5zM98.8 205.4l-.6 .5M100.2 206.7v.1l-.6 .6M101.4 217.4l.5 .5-1.2 1.2 6.4 6.4M101.4 217.4l-1.2 1.2M101.6 217.2l-2.6-2.7-1.5 1.4 3.2 3.2M102.7 215.6l-1.1-.9-1.2 1.2"/>
<path d="M102.7 216l-.3 .4M102.7 214.3a.66 .66 0 0 0-.7 .8M103.5 215.3l-.1-.1-.7 .7M103.5 215.2l-.8-.9-.7 .7 .8 .8M103.8 214.9l.6 .5-1.3 1.3-.5-.5M105.1 212.9l-1-.7-1.7 1.7 .8 .9M105.3 211.8a.66 .66 0 0 0-.7 .7M106.1 212.7l-.9-.9-.6 .7 .9 .8M106.2 210.1l-1.3 1.3 .9 1M106.4 212.4l.5 .5-1.2 1.2-.5-.5M108.8 210l8.5 8.5-8 8M108.8 210l-7.4 7.4"/>
<path d="M108.8 210l-2.6-2.7-1.5 1.4 2.7 2.7M109.3 210.5l-1.2 1.2-.5-.5M110.8 218.7l1.3 1.3M110.9 218.8l-1.9 1.9M111.5 218.1l1.3 1.3M112.9 205.9l.5 .5-1.2 1.2M112.9 205.9l-1.2 1.2M113.1 205.7l-2.7-2.7-1.4 1.5 3.2 3.1M114.1 204.1l-1-.9-1.3 1.3M114.2 202.9a.66 .66 0 0 0-.7 .7M114.3 204.5l-.1-.1-.3 .5M114.5 218.1l1 1h1.2"/>
<path d="M114.9 203.8l-.7 .6M115 203.7l-.8-.8-.7 .6 .8 .8M115.3 203.5l.5 .5-1.2 1.2-.5-.5M115.5 219.1l-6.2 6.2M115.7 216.9l-1.6 1.6-1.5-1.5-5.4 5.3 1.5 1.6-1.6 1.6M116.5 201.5l-.9-.8-1.7 1.7 .7 .9M116.8 200.3a.66 .66 0 0 0-.8 .7M117.6 201.2l-.9-.9-.7 .7 .9 .8M117.9 200.9l.5 .5-1.3 1.3-.5-.6M119.6 215.1l-2.8 2.8M119.8 209.8l1.3 1.3M119.8 212.8l1 1"/>
<path d="M120.4 209.1l1.4 1.3M120.8 213.8v1.2l-.6 .6-1.6-1.6M121.1 211.1l.7-.7 .2 .8-.2 .1zM122.3 207.2l1.3 1.3M122.4 207.3l-1.9 1.9M122.9 206.6l1.3 1.3M123.6 208.5l.6-.6 .3 .7-.1 .2zM126 206.6l1 1M127 207.6h1.2M127 207.6l-6.2 6.2M127.2 205.4l1.6 1.6-8 8M127.2 205.4l-1.6 1.6-1.6-1.5-5.3 5.4 1.5 1.5-1.6 1.6-6.4-6.4"/>
<path d="M243.9 218.3l-.8-.8 1-.9 2.6 2.6-1 .9-.8-.8M244 218.4a.66 .66 0 0 1 .9 0 .66 .66 0 0 1 0 .9M244.3 216l-1.2 1.3 .1 .1M244.5 215.8l3.7-3.7 2.9 3-3.7 3.7zM244.5 215.8l-.2 .2 2.9 2.9 .2-.1M247.2 218.9l-1.2 1.3-.1-.2M248.4 212l2.9 2.9-.2 .2M248.4 212l-.2 .1M249.7 210.9l-.1-.2-1.2 1.3M250.7 211.6l-.9-.8-.9 .9 2.6 2.6 1-.9-.8-.8M250.7 211.7a.66 .66 0 0 0 0 .9 .66 .66 0 0 0 .9 0M252.3 213.5l.2 .2-1.2 1.2"/>
<path d="M36.4 226.6v-2.4h.3v8.3h-3.4v-4.3M36.4 226.6l.3 .9M36.7 225.7l-.3 .8M38.1 225.3h11.4v.7h-11.4zM39.2 225.3v.7M45 226v.3h2.6l1.5 .5v1h-2.5v1.1l-1.9 1.9h-8M46.7 225.3v.7M47 225h-2v.3M47.2 222.4h4.7v.7h-2M49.1 225.3v.7M49.9 222.4v.7h-2.7M62 227.1h15.9v21.1h-15.9z"/>
<path d="M65.4 221.5a1.51 1.51 0 0 0 0 2.5M65.4 227.1v-12.6h1.8v12.6M67.2 221.5a1.51 1.51 0 0 1 0 2.5M72.7 221.5a1.51 1.51 0 0 0 0 2.5M72.7 227.1v-12.6h1.8v12.6M74.5 221.5a1.51 1.51 0 0 1 0 2.5M78.6 220.3v.1h2.1M78.6 220.4v.9h.1M80 221.4l-.3-.4-.3 .1-.1 .3h-.6v-.7h1.9v.7h-.6M80.7 220.4v.9h-.1M80.7 220.3v.1M85.3 229.5v1.4l-.9 .9"/>
<path d="M85.3 230.9h8.7M87.4 229.2h.9l-.3 .7h-.3zM87.4 227.3v1.9M88.3 227.3v1.9M88.3 227.5h2.7M91 229.2h.9l-.3 .7h-.3zM91 227.3v1.9M91.9 227.3v1.9M94 229.5v1.4l.9 .9M108.3 224.3l1 1v1.2l-.6 .6-1.6-1.6M108.3 221.2l1.3 1.3M108.9 220.6l1.3 1.3"/>
<path d="M110.2 221.9l.3 .8-.2 .1-.7-.3M110.2 221.9l-.6 .6M112.1 220l.7-.6 .3 .7-.2 .2zM205.8 226.1a.87 .87 0 0 1 1.3 .4M41.2 243.8l1.8-1.1a.62 .62 0 0 1 .9 .1l1.6 1v2.5l-1.7 .9a.82 .82 0 0 1-1.2-.1l-1.4-.8z"/>
<circle cx="43.3" cy="133" r="3.6"/>
<circle cx="43.3" cy="133" r="6.4"/>
<circle cx="43.3" cy="133" r="2.45"/>
<circle cx="206.6" cy="128.7" r=".84"/>
<circle cx="218.8" cy="135.8" r=".98"/>
<circle cx="238.7" cy="127.7" r=".84"/>
<circle cx="87.5" cy="156.8" r=".43"/>
<circle cx="98" cy="159.1" r=".43"/>
<circle cx="100.6" cy="150.1" r=".46"/>
<circle cx="102.9" cy="154.4" r=".46"/>
<circle cx="184.4" cy="145.1" r=".81"/>
<circle cx="184.4" cy="145.1" r=".65"/>
<circle cx="195.1" cy="156.1" r=".84"/>
<circle cx="217.3" cy="147.3" r=".98"/>
<circle cx="218" cy="141.8" r=".98"/>
<circle cx="224.4" cy="148.1" r=".98"/>
<circle cx="229.7" cy="147.8" r=".98"/>
<circle cx="241.9" cy="153.1" r=".84"/>
<circle cx="260.5" cy="159.2" r=".84"/>
<circle cx="52.3" cy="169.7" r=".67"/>
<circle cx="52.3" cy="175.5" r=".67"/>
<circle cx="71.5" cy="178" r=".43"/>
<circle cx="77.3" cy="164.3" r=".43"/>
<circle cx="82.6" cy="173.6" r=".46"/>
<circle cx="83" cy="170.8" r=".46"/>
<circle cx="83.4" cy="167.9" r=".46"/>
<circle cx="86.2" cy="173.9" r=".46"/>
<circle cx="88.9" cy="173.8" r=".46"/>
<circle cx="93.3" cy="163.7" r=".43"/>
<circle cx="94.9" cy="176.5" r=".43"/>
<circle cx="104.2" cy="179.5" r=".43"/>
<circle cx="107.1" cy="163.7" r=".43"/>
<circle cx="112.7" cy="165" r=".46"/>
<circle cx="127.9" cy="177.3" r=".43"/>
<circle cx="184.9" cy="160.5" r=".44"/>
<circle cx="191.7" cy="164.9" r=".98"/>
<circle cx="225.9" cy="167.9" r=".84"/>
<circle cx="226.3" cy="172.9" r=".98"/>
<circle cx="228.3" cy="162.8" r=".98"/>
<circle cx="234" cy="172.4" r=".98"/>
<circle cx="234" cy="179.4" r=".98"/>
<circle cx="54.5" cy="183.9" r=".46"/>
<circle cx="55.8" cy="189.5" r=".43"/>
<circle cx="60.8" cy="198.5" r=".43"/>
<circle cx="69.8" cy="182.4" r=".46"/>
<circle cx="82.4" cy="196.8" r=".46"/>
<circle cx="85" cy="197.7" r=".46"/>
<circle cx="86.8" cy="195.7" r=".46"/>
<circle cx="86.9" cy="183.9" r=".43"/>
<circle cx="87.1" cy="186.4" r=".46"/>
<circle cx="88.1" cy="181.3" r=".46"/>
<circle cx="89.9" cy="196.4" r=".43"/>
<circle cx="91" cy="186.1" r=".46"/>
<circle cx="91" cy="189.6" r=".46"/>
<circle cx="98.8" cy="193.5" r=".46"/>
<circle cx="103.4" cy="191.3" r=".43"/>
<circle cx="112.1" cy="198.6" r=".43"/>
<circle cx="131.4" cy="189" r="3.6"/>
<circle cx="131.4" cy="189" r="6.4"/>
<circle cx="173.7" cy="197.2" r=".84"/>
<circle cx="216.9" cy="193.8" r=".98"/>
<circle cx="222.1" cy="195.6" r=".98"/>
<circle cx="225.6" cy="191.7" r=".98"/>
<circle cx="232" cy="193" r=".84"/>
<circle cx="249.6" cy="187" r=".98"/>
<circle cx="258.9" cy="182.8" r=".84"/>
<circle cx="54.1" cy="200.2" r=".43"/>
<circle cx="54.5" cy="205.8" r=".43"/>
<circle cx="69.9" cy="218.9" r=".43"/>
<circle cx="77.1" cy="213.3" r=".43"/>
<circle cx="81.2" cy="206.2" r=".43"/>
<circle cx="84" cy="215.1" r=".43"/>
<circle cx="95.5" cy="204" r=".43"/>
<circle cx="105" cy="203.5" r=".43"/>
<circle cx="214.5" cy="212.5" r=".84"/>
<circle cx="243" cy="208.1" r=".84"/>
<circle cx="262.1" cy="207.3" r=".84"/>
<circle cx="53" cy="225.8" r=".43"/>
<circle cx="99" cy="220.4" r=".43"/>
<circle cx="43.3" cy="245" r="3.6"/>
<circle cx="43.3" cy="245" r="6.4"/>
<circle cx="43.3" cy="245" r="2.45"/>
</g>
<g fill="#000">
<circle cx="257.2" cy="179" r=".25"/>
<circle cx="257.2" cy="170.3" r=".25"/>
<circle cx="257.2" cy="173.2" r=".25"/>
<circle cx="257.2" cy="176.1" r=".25"/>
<circle cx="95.7" cy="191.1" r=".25"/>
<circle cx="97.1" cy="191.1" r=".25"/>
<circle cx="98.6" cy="191.1" r=".25"/>
<circle cx="100" cy="191.1" r=".25"/>
<circle cx="102.6" cy="189.4" r=".25"/>
<circle cx="102.6" cy="185.1" r=".25"/>
<circle cx="102.6" cy="186.5" r=".25"/>
<circle cx="102.6" cy="188" r=".25"/>
<circle cx="243.4" cy="182.4" r=".25"/>
<circle cx="246.3" cy="182.4" r=".25"/>
<circle cx="249.1" cy="182.4" r=".25"/>
<circle cx="252" cy="182.4" r=".25"/>
</g>
<g fill="none" stroke="#000" stroke-width=".25">
<path d="M10.3 110.5h279.9v198.8h-279.9zM42.6 107v3.5M78.5 107v3.5M114.4 107v3.5M150.2 107v7.1M186.1 107v3.5M222 107v3.5M257.9 107v3.5M132.4 137.7h-27.8l5.7 25.6M139.1 128.4h21.7l17.5 11M150.6 138.6h11.2l10.5 5.5M215.9 133.7h10.4l2.8 3.6"/>
<path d="M245.5 139.9h13.1l9.5 19.9M6.7 141.3h3.6M94.6 152.4l-1.8 6.5M139 149h22.1l15.9 8.4M248.7 149.1h-10.7l-4.6 4.5M254.2 157.5h-11.2l-6.9 7.2M290.2 141.3h3.6M6.7 175.6h3.6M145.5 163.5h14.9l13.4 6.6M290.2 175.6h3.6M186.4 190.8l-15.2 19.8h-33.3M197.8 199l-5.1 7.5h-6.4"/>
<path d="M226 187.7l-3.5 2.5h-11.9M242.9 197.4l-5.5 7.8h-28.2M267.7 199.4l-14.1 30.9h-2.5M289.9 180.3h-10.7l-9.4 3M6.7 209.9h7.2M249.9 219l1.2 11.3h32.5M286.6 209.9h7.2M80.9 223.9l4.7 33.8h32.6M6.7 244.3h3.6M290.2 244.3h3.6M6.7 278.6h3.6M290.2 278.6h3.6"/>
<path d="M42.6 309.3v3.6M78.5 309.3v3.6M114.4 309.3v3.6M150.2 305.7v7.2M186.1 309.3v3.6M222 309.3v3.6M257.9 309.3v3.6"/>
<circle cx="85.1" cy="186" r="28.2"/>
</g>
<path d="M161 275.6h129.2v33.7h-129.2zM178.2 275.6v7.2M202.6 275.6v33.7M246.4 275.6v33.7M161 282.8h129.2M202.6 289.9h87.6M246.4 302.1h43.8M253.6 302.1v7.2M279.4 302.1v7.2" fill="none" stroke="#000" stroke-width=".34"/>
<g fill="#000" stroke="#000" stroke-width=".18">
<path d="M203.5 279.1h.9l.4 .3h-1v.9l.9 .1-.2 .2h-.7v1h-.3z" fill-rule="evenodd"/>
<path d="M204.2 279.4h.6l.1 .6-.2 .4-.9-.1h.5l.3-.1v-.5l-.2-.3z" fill-rule="evenodd"/>
<path d="M205 279.8h.2l.4 1.5-.2 .3z" fill-rule="evenodd"/>
<path d="M205.9 279.8h.2l-.5 2.2-.4 .1 .2-.2z" fill-rule="evenodd"/>
<path d="M206.3 279.8h.2v.3h.2l-.2 .4v1.1h-.2z" fill-rule="evenodd"/>
<path d="M206.6 279.9l.3-.1v.4l-.4-.1z" fill-rule="evenodd"/>
<path d="M207.3 279.9l.4-.1 .4 .4 .1 .9-.5 .6h-.3l-.2-.3h.5l.2-.2v-1l-.3-.2h-.4z" fill-rule="evenodd"/>
<path d="M208.4 279.1h.2v.9h.3l-.3 .4v.7l.2 .3h-.2v.2h-.2z" fill-rule="evenodd"/>
<path d="M208.6 280l.3-.2 .3 .1a1.57 1.57 0 0 1 .2 1.5l-.4 .3-.4-.2 .4-.1a.93 .93 0 0 0 0-1.4z" fill-rule="evenodd"/>
<path d="M209.9 279.9l.5-.1 .3 .2 .1 1.6h-.2v-.2h-.3l.2-.2v-.4l-.7-.1 .2-.1a.35 .35 0 0 0 .4-.1 .35 .35 0 0 0 0-.4l-.6-.1z" fill-rule="evenodd"/>
<path d="M212.3 280h.4z" fill-rule="evenodd"/>
<path d="M212.1 279.8h.2v.3h.3l-.3 .3v.7l.3 .3-.3 .1v.9h-.2z" fill-rule="evenodd"/>
<path d="M212.5 279.8a.57 .57 0 0 1 .7 .6v.7l-.2 .4-.4 .2-.3-.2a.78 .78 0 0 0 .7-.6 .78 .78 0 0 0-.2-.8l-.5-.1z" fill-rule="evenodd"/>
<path d="M213.7 279.8h.4l.3 .2h-.5l-.2 .2-.1 .8 .3 .4h-.3l-.2-.3v-.6z" fill-rule="evenodd"/>
<path d="M214.7 279.9l.6-.1 .3 .5h-.3l-.2-.3h-.4z" fill-rule="evenodd"/>
<path d="M216.5 279.1h.9l.4 .3h-1.1v.9l1 .1-.2 .2h-.8v1h-.2z" fill-rule="evenodd"/>
<path d="M217.2 279.4h.6v.6l-.1 .4-1-.1h.6l.3-.1v-.5l-.2-.3z" fill-rule="evenodd"/>
<path d="M218 279.8h.2l.4 1.5-.2 .3z" fill-rule="evenodd"/>
<path d="M218.9 279.8h.2l-.5 2.2-.4 .1 .2-.2z" fill-rule="evenodd"/>
<path d="M219.3 279.8h.2v.3h.2l-.2 .4v1.1h-.2z" fill-rule="evenodd"/>
<path d="M219.6 279.9l.3-.1v.4l-.4-.1z" fill-rule="evenodd"/>
<path d="M220.3 279.9l.4-.1 .4 .4v.9l-.4 .6h-.3l-.2-.3h.5l.2-.2v-1l-.3-.2h-.4z" fill-rule="evenodd"/>
<path d="M221.4 279.1h.2v.9h.3l-.3 .4v.7l.2 .3h-.2v.2h-.2z" fill-rule="evenodd"/>
<path d="M221.8 279.8l.4 .1a1.57 1.57 0 0 1 .2 1.5l-.4 .3-.4-.2 .4-.1a.93 .93 0 0 0 0-1.4h-.4z" fill-rule="evenodd"/>
<path d="M222.9 279.9l.5-.1 .3 .2 .1 1.6h-.2v-.2h-.3l.2-.2v-.4l-.7-.1 .2-.1a.41 .41 0 0 0 .5-.4l-.2-.2h-.5z" fill-rule="evenodd"/>
<path d="M225.3 280h.4z" fill-rule="evenodd"/>
<path d="M225.1 279.8h.2v.3h.3l-.3 .3v.7l.3 .3-.3 .1v.9h-.2z" fill-rule="evenodd"/>
<path d="M225.3 280l.2-.2a.57 .57 0 0 1 .7 .6v.7l-.2 .4-.4 .2-.3-.2a.78 .78 0 0 0 .7-.6 .78 .78 0 0 0-.2-.8z" fill-rule="evenodd"/>
<path d="M226.5 280l.4-.2 .5 .2h-.5l-.2 .3-.1 .7 .3 .4h-.3l-.2-.3z" fill-rule="evenodd"/>
<path d="M227.7 279.9l.6-.1 .3 .5h-.3l-.2-.3h-.4z" fill-rule="evenodd"/>
<path d="M205.1 282.1h.4l-.3 .3h-.1z" fill-rule="evenodd"/>
<path d="M203.7 293.8h2.4v.5h-2v1.1h1.9v.4h-1.9v1.2h2.1v.4h-2.5z" fill-rule="evenodd"/>
<path d="M206.5 294.9h.5l1.7 2.5h-.5z" fill-rule="evenodd"/>
<path d="M207.1 280.1l.5-.1-.1 .1a.99 .99 0 0 0-.2 1.1l.3 .2h-.4l-.1-.2-.1-.7z" fill-rule="evenodd"/>
<path d="M207.3 296.1l.3 .3-.7 1h-.5z" fill-rule="evenodd"/>
<path d="M208.1 294.9h.5l-.8 1.2-.3-.4z" fill-rule="evenodd"/>
<path d="M208.6 281.4h.4z" fill-rule="evenodd"/>
<path d="M209.1 294.2l.4-.3v1h.3v.3h-.3v1.7l.1 .2h-.5v-1.9h-.3v-.3h.3z" fill-rule="evenodd"/>
<path d="M209.8 280.1l.4-.1-.2 .2-.1 .2-.2-.1z" fill-rule="evenodd"/>
<path d="M209.1 297.1h.7l.1 .3a.56 .56 0 0 1-.8-.3z" fill-rule="evenodd"/>
<path d="M209.8 280.8h.7h-.1a.36 .36 0 0 0-.4 .2 .36 .36 0 0 0 .1 .4l.4 .1-.3 .2-.3-.1-.2-.3z" fill-rule="evenodd"/>
<path d="M210.1 281.4h.5z" fill-rule="evenodd"/>
<path d="M210.3 294.9h.3v.3h.4l-.2 .2-.1 .4v1.6h-.4z" fill-rule="evenodd"/>
<path d="M211.1 279.1h.2v2.5h-.2z" fill-rule="evenodd"/>
<path d="M210.9 294.9l.3-.1 .3 .1-.1 .4-.8-.1z" fill-rule="evenodd"/>
<path d="M211.6 279.1h.2v2.5h-.2z" fill-rule="evenodd"/>
<path d="M211.8 294.9h.4l.1 2 .2 .2h.8l-.4 .3h-.7l-.4-.5z" fill-rule="evenodd"/>
<path d="M212.7 297.1h.6z" fill-rule="evenodd"/>
<path d="M213.3 294.9h.4v2.5h-.4v-.3l-.3-.1 .3-.4z" fill-rule="evenodd"/>
<path d="M213.6 281.4h.4l.2-.4h.3l-.2 .5-.2 .2h-.3z" fill-rule="evenodd"/>
<path d="M214 280h.4l.1 .4h-.3z" fill-rule="evenodd"/>
<path d="M214.6 280.1l.5-.1-.2 .1a.41 .41 0 0 0 .4 .5l.3 .4-.1 .5-.3 .2h-.3l-.2-.3h.5a.37 .37 0 0 0 .1-.4 .37 .37 0 0 0-.4-.2l-.3-.3z" fill-rule="evenodd"/>
<path d="M214.6 281.1h.2l.2 .3h-.3z" fill-rule="evenodd"/>
<path d="M214.4 295.1l.7-.3h.3l.4 .3-.8 .1-.3 .3-.1 1.1 .2 .3 .3 .2h-.6l-.2-.3-.1-.8z" fill-rule="evenodd"/>
<path d="M214.5 297.1h1.4a.8 .8 0 0 1-1.2 .2z" fill-rule="evenodd"/>
<path d="M215.8 293.8h.4v3.6h-.3v-.3h-.5l.2-.1 .3-.5-.1-.8-.5-.6h.5z" fill-rule="evenodd"/>
<path d="M217 295.2l.8-.1a.67 .67 0 0 0-.6 .8h1.7v.3h-1.8l.2 .7 .5 .2h-.8l-.3-.6v-.7z" fill-rule="evenodd"/>
<path d="M217.1 295.1a1.03 1.03 0 0 1 1.6 .1l.2 .7h-1.7l1.3-.1-.3-.5-.2-.2h-1z" fill-rule="evenodd"/>
<path d="M218.1 282.1h.4l-.3 .3h-.1z" fill-rule="evenodd"/>
<path d="M217 297.1h1.1l.4-.5 .4 .1a1.06 1.06 0 0 1-1.4 .7z" fill-rule="evenodd"/>
<path d="M219.4 294.9h.4v.3h.4l-.3 .2-.1 .4v1.6h-.4z" fill-rule="evenodd"/>
<path d="M220.1 280.1l.5-.1-.1 .1a.99 .99 0 0 0-.2 1.1l.3 .2h-.4l-.2-.2v-.7z" fill-rule="evenodd"/>
<path d="M219.9 294.9l.4-.1 .4 .1-.1 .4-.8-.1z" fill-rule="evenodd"/>
<path d="M220.6 298.1h2.6v.4h-2.6z" fill-rule="evenodd"/>
<path d="M221.6 281.4h.4z" fill-rule="evenodd"/>
<path d="M222.8 280.1l.4-.1-.2 .2-.1 .2-.2-.1z" fill-rule="evenodd"/>
<path d="M222.8 280.8h.7h-.1a.36 .36 0 0 0-.5 .2 .36 .36 0 0 0 .2 .4l.4 .1-.3 .2-.3-.1-.2-.3z" fill-rule="evenodd"/>
<path d="M223.1 281.4h.5z" fill-rule="evenodd"/>
<path d="M224.1 279.1h.2v2.5h-.2z" fill-rule="evenodd"/>
<path d="M224.6 279.1h.2v2.5h-.2z" fill-rule="evenodd"/>
<path d="M223.5 293.8l1.6 .1 .6 .4h-1.8v1.1h1.6l-.2 .1 .5 .3h-1.9v1.2l1.9 .1-.2 .2-.6 .1h-1.5z" fill-rule="evenodd"/>
<path d="M224.7 294.3h1l.1 .3v.4l-.3 .4h-1.6h1a.55 .55 0 0 0 .5-.7 .55 .55 0 0 0-.7-.4z" fill-rule="evenodd"/>
<path d="M225 295.8h.8l.2 .7-.2 .6-1.9-.1h1.1l.5-.3v-.5l-.1-.2z" fill-rule="evenodd"/>
<path d="M226.6 295.2l.9-.1-.5 .3-.2 .5 .1 1 .6 .2h-.8l-.3-.3v-.9z" fill-rule="evenodd"/>
<path d="M226.6 281.4h.4l.2-.4h.3l-.1 .3-.3 .4h-.3z" fill-rule="evenodd"/>
<path d="M227 280h.4l.1 .4h-.3z" fill-rule="evenodd"/>
<path d="M226.7 295.1l.2-.2a1.21 1.21 0 0 1 1.4 .3l.2 .3a1.45 1.45 0 0 1-.8 2h-.5l-.5-.4h1.1l.3-.6a1.03 1.03 0 0 0-.5-1.4z" fill-rule="evenodd"/>
<path d="M227.6 280.1l.5-.1-.2 .1a.41 .41 0 0 0 .4 .5l.3 .4-.1 .5-.3 .2h-.3l-.2-.3h.5a.37 .37 0 0 0 .1-.4 .37 .37 0 0 0-.4-.2l-.3-.3z" fill-rule="evenodd"/>
<path d="M227.6 281.1h.2l.2 .3h-.3z" fill-rule="evenodd"/>
<path d="M229.1 295.2l.9-.1a.59 .59 0 0 0-.6 .6l-.4-.1z" fill-rule="evenodd"/>
<path d="M229.3 296.1h1.2l-.7 .2a.41 .41 0 0 0-.4 .5 .41 .41 0 0 0 .4 .3l.7 .1a.98 .98 0 0 1-1.6-.2l.1-.6z" fill-rule="evenodd"/>
<path d="M229.2 295.1a1.09 1.09 0 0 1 1.8 .3v1.6l.1 .4h-.4l-.1-.3h-.5l.4-.4v-.6h-1.2l1.1-.2a.39 .39 0 0 0 .1-.5 .39 .39 0 0 0-.3-.3z" fill-rule="evenodd"/>
<path d="M229.8 297.1h.8z" fill-rule="evenodd"/>
<path d="M231.6 294.9h.3v.3h.5l-.3 .2-.1 .4v1.6h-.4z" fill-rule="evenodd"/>
<path d="M232.2 294.9l.3-.1 .4 .1-.2 .4-.8-.1z" fill-rule="evenodd"/>
<path d="M233.2 295.1l.6-.3 .5 .1 .3 .2-.8 .1-.3 .3-.1 1.1 .2 .3 .3 .2h-.6l-.2-.3-.1-.8z" fill-rule="evenodd"/>
<path d="M233.3 297.1h1.4a.8 .8 0 0 1-1.2 .2z" fill-rule="evenodd"/>
<path d="M234.6 293.8h.4v3.6h-.3v-.3h-.5l.2-.1 .3-.5-.1-.8-.5-.6h.5z" fill-rule="evenodd"/>
<path d="M235.8 294.7l.3-.1h.5l-.7 .5z" fill-rule="evenodd"/>
<path d="M236.8 293.8h.3v3.6h-.5v-2.8h-.5z" fill-rule="evenodd"/>
<path d="M238.3 296.9h.5v.5h-.5z" fill-rule="evenodd"/>
<path d="M239.6 294.7l.3-.1h.6l-.8 .5z" fill-rule="evenodd"/>
<path d="M240.6 293.8h.3v3.6h-.4v-2.8h-.6z" fill-rule="evenodd"/>
<path d="M242.1 296.9h.5v.5h-.5z" fill-rule="evenodd"/>
<path d="M243.5 294.2h.7a.82 .82 0 0 0-.6 1v1.3l.3 .5 .3 .1-.7 .1-.3-.6v-1.3z" fill-rule="evenodd"/>
<path d="M243.5 294.2a.95 .95 0 0 1 1-.4 .95 .95 0 0 1 .7 .8l.1 1.1-.1 .8a1.14 1.14 0 0 1-.7 1h-.5l-.5-.3a1.16 1.16 0 0 0 1.2-.3l.2-.9-.1-1.4-.5-.4z" fill-rule="evenodd"/>
</g>
<g fill="#000">
<path d="M178.5 139.1l1.9 1.7-2.3-1zM228.8 137.5l.6-.5 1.2 2.2zM172.6 143.8l2 1.5-2.4-.8zM177.2 157.1l2.1 1.5-2.4-.8zM233.1 153.3l.6 .6-2.1 1.4zM267.8 159.9l.7-.3 .7 2.4zM109.9 163.4l.8-.2 .1 2.5zM173.9 169.8l2.1 1.4-2.4-.7zM235.8 164.4l.5 .6-2 1.5zM186.1 190.5l1.9-1.7-1.2 2.2zM199.2 196.9l-1 2.4-.8-.5zM225.8 187.3l2.2-1.1-1.8 1.8z"/>
<path d="M242.6 197.2l1.7-1.8-1.1 2.3zM268.7 197.1l-.6 2.5-.8-.3zM267.4 184l2.3-1.2 .3 .8zM249.6 216.5l.7 2.5-.8 .1zM80.6 221.4l.7 2.4-.8 .1z"/>
</g>
<use href="#words"/>
</svg>
